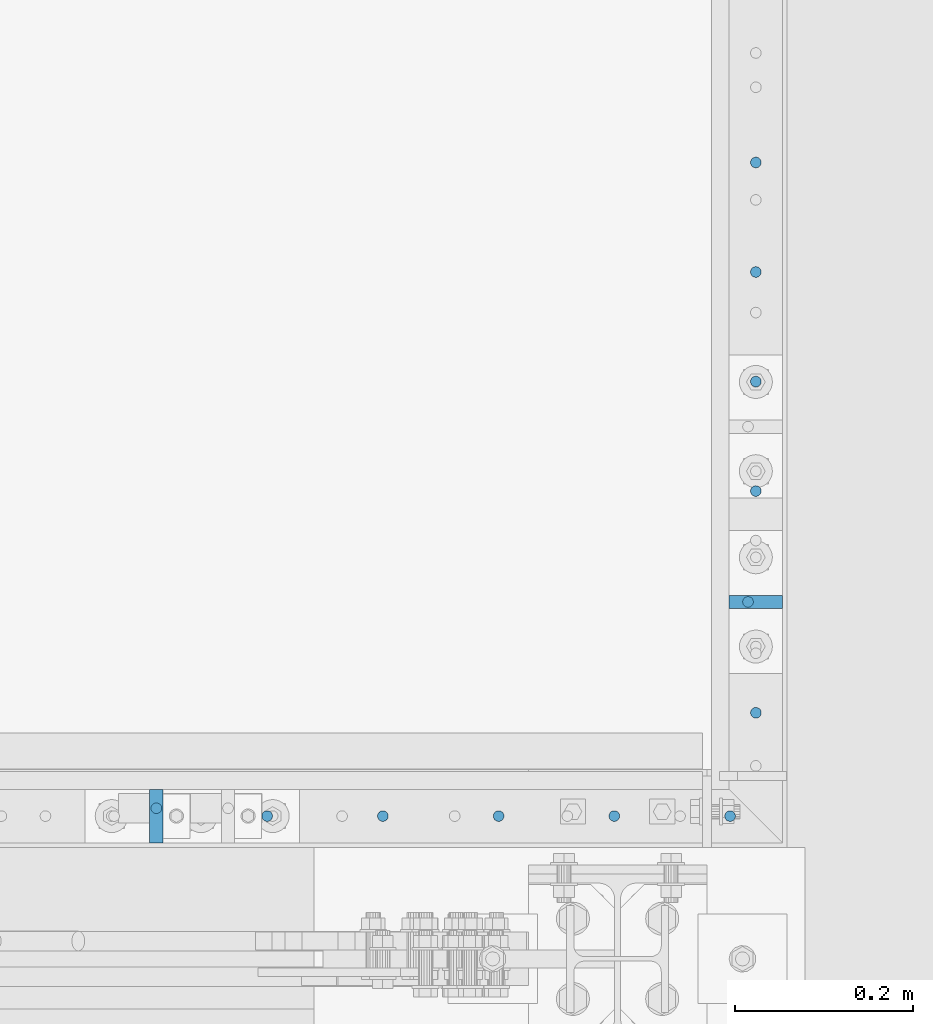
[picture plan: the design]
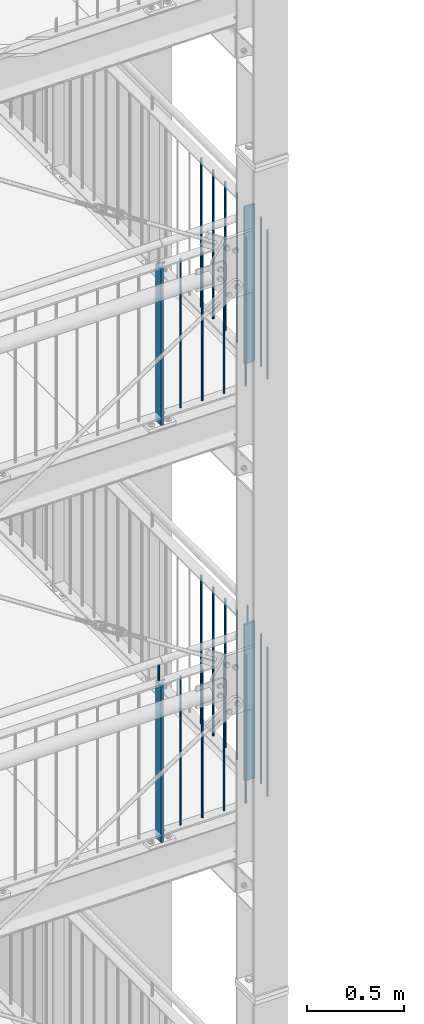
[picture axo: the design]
# One storey, part 88 of 825: 26 columns.
"""IFC2X3 building model written with IfcOpenShell, lengths in millimetres."""

from ifc_helpers import new_model, entity, si_unit, converted_unit, frame, origin, origin_with_axes, origin_2d, place, context, project, spatial, rectangle, circle, extrude, clip, halfspace, material, element, save


model = new_model("IFC2X3")

# Units and contexts
model_context = context("Model", 3, precision=1e-09, world=origin_with_axes())
ifc_project = project(units=[si_unit("LENGTHUNIT", "METRE", prefix="MILLI"), si_unit("AREAUNIT", "SQUARE_METRE"), si_unit("VOLUMEUNIT", "CUBIC_METRE"), converted_unit("PLANEANGLEUNIT", "DEGREE", entity("IfcPlaneAngleMeasure", 0.01745329), si_unit("PLANEANGLEUNIT", "RADIAN"), dimensions=[0, 0, 0, 0, 0, 0, 0])], contexts=[model_context])

# Site, building, storey
site_placement = place(None, origin_with_axes())
site = spatial("IfcSite", under=ifc_project, at=site_placement, CompositionType="ELEMENT")
building_placement = place(site_placement, origin_with_axes())
building = spatial("IfcBuilding", under=site, at=building_placement, Name="1", CompositionType="ELEMENT")
storey_placement = place(building_placement, origin_with_axes())
storey = spatial("IfcBuildingStorey", under=building, at=storey_placement, Name="Default Storey", CompositionType="ELEMENT", Elevation=0.0)

# Columns
ifc_material = material(Name="S235JR")
column_1_placement = place(None, frame((9021.713402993, 4766.735971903, 9675.723292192), z_axis=(0.0, 0.0, 1.0), x_axis=(0.0, -1.0, 0.0)))
element("IfcColumn", 1, at=column_1_placement, inside=storey, material=ifc_material, Name="Railing_Post_Landing#7", ObjectType="Railing_Post_Landing#7", context=model_context, shape_type="Clipping", body=[
    clip(clip(extrude(rectangle(XDim=15.0, YDim=60.0, at=origin_2d()), origin(), (0.0, 0.0, -1.0), 1070.646584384), halfspace(frame((4766.735971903, -9021.713402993, -1019.722292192), z_axis=(0.0, 0.0, 1.0), x_axis=(0.0, 1.0, 0.0)), True)), halfspace(frame((4766.735971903, -9021.713402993, -30.924292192), z_axis=(0.0, 0.0, -1.0), x_axis=(0.0, -1.0, 0.0)), True)),
])
column_2_placement = place(None, frame((8349.792260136, 4526.736971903, 9675.723292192), z_axis=(0.0, 0.0, 1.0), x_axis=(-1.0, 0.0, 0.0)))
element("IfcColumn", 2, at=column_2_placement, inside=storey, material=ifc_material, Name="Railing_Post_Landing#8", ObjectType="Railing_Post_Landing#8", context=model_context, shape_type="Clipping", body=[
    clip(clip(extrude(rectangle(XDim=15.0, YDim=60.0, at=origin_2d()), origin(), (0.0, 0.0, -1.0), 1070.646584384), halfspace(frame((8349.792260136, 4526.736971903, -1019.722292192), z_axis=(0.0, 0.0, 1.0), x_axis=(-1.0, 0.0, 0.0)), True)), halfspace(frame((8349.792260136, 4526.736971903, -30.924292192), z_axis=(0.0, 0.0, -1.0), x_axis=(1.0, 0.0, 0.0)), True)),
])
column_3_placement = place(None, frame((9021.713402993, 5259.236043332, 9658.285281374), z_axis=(0.0, 0.0, 1.0), x_axis=(0.0, -1.0, 0.0)))
element("IfcColumn", 3, at=column_3_placement, inside=storey, material=ifc_material, Name="Railing_Picket_Landing#45", ObjectType="Railing_Picket_Landing#45", context=model_context, shape_type="Clipping", body=[
    clip(clip(extrude(circle(Radius=6.0, at=origin_2d()), origin(), (0.0, 0.0, -1.0), 965.770562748), halfspace(frame((5259.236043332, -9021.713402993, -13.486281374), z_axis=(0.0, 0.0, -1.0), x_axis=(0.0, -1.0, 0.0)), True)), halfspace(frame((5259.236043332, -9021.713402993, -952.284281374), z_axis=(0.0, 0.0, 1.0), x_axis=(0.0, 1.0, 0.0)), True)),
])
column_4_placement = place(None, frame((9021.713402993, 5136.486019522, 9658.285281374), z_axis=(0.0, 0.0, 1.0), x_axis=(0.0, -1.0, 0.0)))
element("IfcColumn", 4, at=column_4_placement, inside=storey, material=ifc_material, Name="Railing_Picket_Landing#46", ObjectType="Railing_Picket_Landing#46", context=model_context, shape_type="Clipping", body=[
    clip(clip(extrude(circle(Radius=6.0, at=origin_2d()), origin(), (0.0, 0.0, -1.0), 965.770562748), halfspace(frame((5136.486019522, -9021.713402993, -13.486281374), z_axis=(0.0, 0.0, -1.0), x_axis=(0.0, -1.0, 0.0)), True)), halfspace(frame((5136.486019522, -9021.713402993, -952.284281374), z_axis=(0.0, 0.0, 1.0), x_axis=(0.0, 1.0, 0.0)), True)),
])
column_5_placement = place(None, frame((9021.713402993, 5013.735995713, 9658.285281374), z_axis=(0.0, 0.0, 1.0), x_axis=(0.0, -1.0, 0.0)))
element("IfcColumn", 5, at=column_5_placement, inside=storey, material=ifc_material, Name="Railing_Picket_Landing#47", ObjectType="Railing_Picket_Landing#47", context=model_context, shape_type="Clipping", body=[
    clip(clip(extrude(circle(Radius=6.0, at=origin_2d()), origin(), (0.0, 0.0, -1.0), 965.770562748), halfspace(frame((5013.735995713, -9021.713402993, -13.486281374), z_axis=(0.0, 0.0, -1.0), x_axis=(0.0, -1.0, 0.0)), True)), halfspace(frame((5013.735995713, -9021.713402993, -952.284281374), z_axis=(0.0, 0.0, 1.0), x_axis=(0.0, 1.0, 0.0)), True)),
])
column_6_placement = place(None, frame((9021.713402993, 4890.985971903, 9658.285281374), z_axis=(0.0, 0.0, 1.0), x_axis=(0.0, -1.0, 0.0)))
element("IfcColumn", 6, at=column_6_placement, inside=storey, material=ifc_material, Name="Railing_Picket_Landing#48", ObjectType="Railing_Picket_Landing#48", context=model_context, shape_type="Clipping", body=[
    clip(clip(extrude(circle(Radius=6.0, at=origin_2d()), origin(), (0.0, 0.0, -1.0), 965.770562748), halfspace(frame((4890.985971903, -9021.713402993, -13.486281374), z_axis=(0.0, 0.0, -1.0), x_axis=(0.0, -1.0, 0.0)), True)), halfspace(frame((4890.985971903, -9021.713402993, -952.284281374), z_axis=(0.0, 0.0, 1.0), x_axis=(0.0, 1.0, 0.0)), True)),
])
column_7_placement = place(None, frame((9021.713402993, 4642.485971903, 9658.285281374), z_axis=(0.0, 0.0, 1.0), x_axis=(0.0, -1.0, 0.0)))
element("IfcColumn", 7, at=column_7_placement, inside=storey, material=ifc_material, Name="Railing_Picket_Landing#49", ObjectType="Railing_Picket_Landing#49", context=model_context, shape_type="Clipping", body=[
    clip(clip(extrude(circle(Radius=6.0, at=origin_2d()), origin(), (0.0, 0.0, -1.0), 965.770562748), halfspace(frame((4642.485971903, -9021.713402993, -13.486281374), z_axis=(0.0, 0.0, -1.0), x_axis=(0.0, -1.0, 0.0)), True)), halfspace(frame((4642.485971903, -9021.713402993, -952.284281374), z_axis=(0.0, 0.0, 1.0), x_axis=(0.0, 1.0, 0.0)), True)),
])
column_8_placement = place(None, frame((8992.778374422, 4526.736971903, 9658.285281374), z_axis=(0.0, 0.0, 1.0), x_axis=(-1.0, 0.0, 0.0)))
element("IfcColumn", 8, at=column_8_placement, inside=storey, material=ifc_material, Name="Railing_Picket_Landing#50", ObjectType="Railing_Picket_Landing#50", context=model_context, shape_type="Clipping", body=[
    clip(clip(extrude(circle(Radius=6.0, at=origin_2d()), origin(), (0.0, 0.0, -1.0), 965.770562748), halfspace(frame((8992.778374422, 4526.736971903, -13.486281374), z_axis=(0.0, 0.0, -1.0), x_axis=(1.0, 0.0, 0.0)), True)), halfspace(frame((8992.778374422, 4526.736971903, -952.284281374), z_axis=(0.0, 0.0, 1.0), x_axis=(-1.0, 0.0, 0.0)), True)),
])
column_9_placement = place(None, frame((8863.09434585, 4526.736971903, 9658.285281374), z_axis=(0.0, 0.0, 1.0), x_axis=(-1.0, 0.0, 0.0)))
element("IfcColumn", 9, at=column_9_placement, inside=storey, material=ifc_material, Name="Railing_Picket_Landing#51", ObjectType="Railing_Picket_Landing#51", context=model_context, shape_type="Clipping", body=[
    clip(clip(extrude(circle(Radius=6.0, at=origin_2d()), origin(), (0.0, 0.0, -1.0), 965.770562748), halfspace(frame((8863.09434585, 4526.736971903, -13.486281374), z_axis=(0.0, 0.0, -1.0), x_axis=(1.0, 0.0, 0.0)), True)), halfspace(frame((8863.09434585, 4526.736971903, -952.284281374), z_axis=(0.0, 0.0, 1.0), x_axis=(-1.0, 0.0, 0.0)), True)),
])
column_10_placement = place(None, frame((8733.410317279, 4526.736971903, 9658.285281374), z_axis=(0.0, 0.0, 1.0), x_axis=(-1.0, 0.0, 0.0)))
element("IfcColumn", 10, at=column_10_placement, inside=storey, material=ifc_material, Name="Railing_Picket_Landing#52", ObjectType="Railing_Picket_Landing#52", context=model_context, shape_type="Clipping", body=[
    clip(clip(extrude(circle(Radius=6.0, at=origin_2d()), origin(), (0.0, 0.0, -1.0), 965.770562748), halfspace(frame((8733.410317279, 4526.736971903, -13.486281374), z_axis=(0.0, 0.0, -1.0), x_axis=(1.0, 0.0, 0.0)), True)), halfspace(frame((8733.410317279, 4526.736971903, -952.284281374), z_axis=(0.0, 0.0, 1.0), x_axis=(-1.0, 0.0, 0.0)), True)),
])
column_11_placement = place(None, frame((8603.726288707, 4526.736971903, 9658.285281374), z_axis=(0.0, 0.0, 1.0), x_axis=(-1.0, 0.0, 0.0)))
element("IfcColumn", 11, at=column_11_placement, inside=storey, material=ifc_material, Name="Railing_Picket_Landing#53", ObjectType="Railing_Picket_Landing#53", context=model_context, shape_type="Clipping", body=[
    clip(clip(extrude(circle(Radius=6.0, at=origin_2d()), origin(), (0.0, 0.0, -1.0), 965.770562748), halfspace(frame((8603.726288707, 4526.736971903, -13.486281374), z_axis=(0.0, 0.0, -1.0), x_axis=(1.0, 0.0, 0.0)), True)), halfspace(frame((8603.726288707, 4526.736971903, -952.284281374), z_axis=(0.0, 0.0, 1.0), x_axis=(-1.0, 0.0, 0.0)), True)),
])
column_12_placement = place(None, frame((8474.042260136, 4526.736971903, 9658.285281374), z_axis=(0.0, 0.0, 1.0), x_axis=(-1.0, 0.0, 0.0)))
element("IfcColumn", 12, at=column_12_placement, inside=storey, material=ifc_material, Name="Railing_Picket_Landing#54", ObjectType="Railing_Picket_Landing#54", context=model_context, shape_type="Clipping", body=[
    clip(clip(extrude(circle(Radius=6.0, at=origin_2d()), origin(), (0.0, 0.0, -1.0), 965.770562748), halfspace(frame((8474.042260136, 4526.736971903, -13.486281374), z_axis=(0.0, 0.0, -1.0), x_axis=(1.0, 0.0, 0.0)), True)), halfspace(frame((8474.042260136, 4526.736971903, -952.284281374), z_axis=(0.0, 0.0, 1.0), x_axis=(-1.0, 0.0, 0.0)), True)),
])
column_13_placement = place(None, frame((9012.913402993, 4766.735971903, 9763.285281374), z_axis=(0.0, 0.0, 1.0), x_axis=(-1.0, 0.0, 0.0)))
element("IfcColumn", 13, at=column_13_placement, inside=storey, material=ifc_material, Name="Bar#7", ObjectType="Bar#7", context=model_context, shape_type="Clipping", body=[
    clip(clip(extrude(circle(Radius=6.0, at=origin_2d()), origin(), (0.0, 0.0, -1.0), 116.970562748), halfspace(frame((9012.913402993, 4766.735971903, -8.486281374), z_axis=(0.0, 0.0, -1.0), x_axis=(1.0, 0.0, 0.0)), True)), halfspace(frame((9012.913402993, 4766.735971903, -108.484281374), z_axis=(0.0, 0.0, 1.0), x_axis=(-1.0, 0.0, 0.0)), True)),
])
column_14_placement = place(None, frame((8349.792260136, 4535.536971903, 9763.285281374), z_axis=(0.0, 0.0, 1.0), x_axis=(0.0, 1.0, 0.0)))
element("IfcColumn", 14, at=column_14_placement, inside=storey, material=ifc_material, Name="Bar#8", ObjectType="Bar#8", context=model_context, shape_type="Clipping", body=[
    clip(clip(extrude(circle(Radius=6.0, at=origin_2d()), origin(), (0.0, 0.0, -1.0), 116.970562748), halfspace(frame((-4535.536971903, 8349.792260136, -8.486281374), z_axis=(0.0, 0.0, -1.0), x_axis=(0.0, 1.0, 0.0)), True)), halfspace(frame((-4535.536971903, 8349.792260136, -108.484281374), z_axis=(0.0, 0.0, 1.0), x_axis=(0.0, -1.0, 0.0)), True)),
])
column_15_placement = place(None, frame((9021.713402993, 4766.735971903, 12305.223292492), z_axis=(0.0, 0.0, 1.0), x_axis=(0.0, -1.0, 0.0)))
element("IfcColumn", 15, at=column_15_placement, inside=storey, material=ifc_material, Name="Railing_Post_Landing#7", ObjectType="Railing_Post_Landing#7", context=model_context, shape_type="Clipping", body=[
    clip(clip(extrude(rectangle(XDim=15.0, YDim=60.0, at=origin_2d()), origin(), (0.0, 0.0, -1.0), 1070.646584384), halfspace(frame((4766.735971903, -9021.713402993, -1019.722292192), z_axis=(0.0, 0.0, 1.0), x_axis=(0.0, 1.0, 0.0)), True)), halfspace(frame((4766.735971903, -9021.713402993, -30.924292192), z_axis=(0.0, 0.0, -1.0), x_axis=(0.0, -1.0, 0.0)), True)),
])
column_16_placement = place(None, frame((8349.792260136, 4526.736971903, 12305.223292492), z_axis=(0.0, 0.0, 1.0), x_axis=(-1.0, 0.0, 0.0)))
element("IfcColumn", 16, at=column_16_placement, inside=storey, material=ifc_material, Name="Railing_Post_Landing#8", ObjectType="Railing_Post_Landing#8", context=model_context, shape_type="Clipping", body=[
    clip(clip(extrude(rectangle(XDim=15.0, YDim=60.0, at=origin_2d()), origin(), (0.0, 0.0, -1.0), 1070.646584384), halfspace(frame((8349.792260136, 4526.736971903, -1019.722292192), z_axis=(0.0, 0.0, 1.0), x_axis=(-1.0, 0.0, 0.0)), True)), halfspace(frame((8349.792260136, 4526.736971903, -30.924292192), z_axis=(0.0, 0.0, -1.0), x_axis=(1.0, 0.0, 0.0)), True)),
])
column_17_placement = place(None, frame((9021.713402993, 5259.236043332, 12287.785281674), z_axis=(0.0, 0.0, 1.0), x_axis=(0.0, -1.0, 0.0)))
element("IfcColumn", 17, at=column_17_placement, inside=storey, material=ifc_material, Name="Railing_Picket_Landing#45", ObjectType="Railing_Picket_Landing#45", context=model_context, shape_type="Clipping", body=[
    clip(clip(extrude(circle(Radius=6.0, at=origin_2d()), origin(), (0.0, 0.0, -1.0), 965.770562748), halfspace(frame((5259.236043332, -9021.713402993, -13.486281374), z_axis=(0.0, 0.0, -1.0), x_axis=(0.0, -1.0, 0.0)), True)), halfspace(frame((5259.236043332, -9021.713402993, -952.284281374), z_axis=(0.0, 0.0, 1.0), x_axis=(0.0, 1.0, 0.0)), True)),
])
column_18_placement = place(None, frame((9021.713402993, 5136.486019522, 12287.785281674), z_axis=(0.0, 0.0, 1.0), x_axis=(0.0, -1.0, 0.0)))
element("IfcColumn", 18, at=column_18_placement, inside=storey, material=ifc_material, Name="Railing_Picket_Landing#46", ObjectType="Railing_Picket_Landing#46", context=model_context, shape_type="Clipping", body=[
    clip(clip(extrude(circle(Radius=6.0, at=origin_2d()), origin(), (0.0, 0.0, -1.0), 965.770562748), halfspace(frame((5136.486019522, -9021.713402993, -13.486281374), z_axis=(0.0, 0.0, -1.0), x_axis=(0.0, -1.0, 0.0)), True)), halfspace(frame((5136.486019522, -9021.713402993, -952.284281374), z_axis=(0.0, 0.0, 1.0), x_axis=(0.0, 1.0, 0.0)), True)),
])
column_19_placement = place(None, frame((9021.713402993, 5013.735995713, 12287.785281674), z_axis=(0.0, 0.0, 1.0), x_axis=(0.0, -1.0, 0.0)))
element("IfcColumn", 19, at=column_19_placement, inside=storey, material=ifc_material, Name="Railing_Picket_Landing#47", ObjectType="Railing_Picket_Landing#47", context=model_context, shape_type="Clipping", body=[
    clip(clip(extrude(circle(Radius=6.0, at=origin_2d()), origin(), (0.0, 0.0, -1.0), 965.770562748), halfspace(frame((5013.735995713, -9021.713402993, -13.486281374), z_axis=(0.0, 0.0, -1.0), x_axis=(0.0, -1.0, 0.0)), True)), halfspace(frame((5013.735995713, -9021.713402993, -952.284281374), z_axis=(0.0, 0.0, 1.0), x_axis=(0.0, 1.0, 0.0)), True)),
])
column_20_placement = place(None, frame((9021.713402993, 4890.985971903, 12287.785281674), z_axis=(0.0, 0.0, 1.0), x_axis=(0.0, -1.0, 0.0)))
element("IfcColumn", 20, at=column_20_placement, inside=storey, material=ifc_material, Name="Railing_Picket_Landing#48", ObjectType="Railing_Picket_Landing#48", context=model_context, shape_type="Clipping", body=[
    clip(clip(extrude(circle(Radius=6.0, at=origin_2d()), origin(), (0.0, 0.0, -1.0), 965.770562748), halfspace(frame((4890.985971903, -9021.713402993, -13.486281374), z_axis=(0.0, 0.0, -1.0), x_axis=(0.0, -1.0, 0.0)), True)), halfspace(frame((4890.985971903, -9021.713402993, -952.284281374), z_axis=(0.0, 0.0, 1.0), x_axis=(0.0, 1.0, 0.0)), True)),
])
column_21_placement = place(None, frame((9021.713402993, 4642.485971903, 12287.785281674), z_axis=(0.0, 0.0, 1.0), x_axis=(0.0, -1.0, 0.0)))
element("IfcColumn", 21, at=column_21_placement, inside=storey, material=ifc_material, Name="Railing_Picket_Landing#49", ObjectType="Railing_Picket_Landing#49", context=model_context, shape_type="Clipping", body=[
    clip(clip(extrude(circle(Radius=6.0, at=origin_2d()), origin(), (0.0, 0.0, -1.0), 965.770562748), halfspace(frame((4642.485971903, -9021.713402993, -13.486281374), z_axis=(0.0, 0.0, -1.0), x_axis=(0.0, -1.0, 0.0)), True)), halfspace(frame((4642.485971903, -9021.713402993, -952.284281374), z_axis=(0.0, 0.0, 1.0), x_axis=(0.0, 1.0, 0.0)), True)),
])
column_22_placement = place(None, frame((8992.778374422, 4526.736971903, 12287.785281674), z_axis=(0.0, 0.0, 1.0), x_axis=(-1.0, 0.0, 0.0)))
element("IfcColumn", 22, at=column_22_placement, inside=storey, material=ifc_material, Name="Railing_Picket_Landing#50", ObjectType="Railing_Picket_Landing#50", context=model_context, shape_type="Clipping", body=[
    clip(clip(extrude(circle(Radius=6.0, at=origin_2d()), origin(), (0.0, 0.0, -1.0), 965.770562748), halfspace(frame((8992.778374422, 4526.736971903, -13.486281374), z_axis=(0.0, 0.0, -1.0), x_axis=(1.0, 0.0, 0.0)), True)), halfspace(frame((8992.778374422, 4526.736971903, -952.284281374), z_axis=(0.0, 0.0, 1.0), x_axis=(-1.0, 0.0, 0.0)), True)),
])
column_23_placement = place(None, frame((8863.09434585, 4526.736971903, 12287.785281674), z_axis=(0.0, 0.0, 1.0), x_axis=(-1.0, 0.0, 0.0)))
element("IfcColumn", 23, at=column_23_placement, inside=storey, material=ifc_material, Name="Railing_Picket_Landing#51", ObjectType="Railing_Picket_Landing#51", context=model_context, shape_type="Clipping", body=[
    clip(clip(extrude(circle(Radius=6.0, at=origin_2d()), origin(), (0.0, 0.0, -1.0), 965.770562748), halfspace(frame((8863.09434585, 4526.736971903, -13.486281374), z_axis=(0.0, 0.0, -1.0), x_axis=(1.0, 0.0, 0.0)), True)), halfspace(frame((8863.09434585, 4526.736971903, -952.284281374), z_axis=(0.0, 0.0, 1.0), x_axis=(-1.0, 0.0, 0.0)), True)),
])
column_24_placement = place(None, frame((8733.410317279, 4526.736971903, 12287.785281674), z_axis=(0.0, 0.0, 1.0), x_axis=(-1.0, 0.0, 0.0)))
element("IfcColumn", 24, at=column_24_placement, inside=storey, material=ifc_material, Name="Railing_Picket_Landing#52", ObjectType="Railing_Picket_Landing#52", context=model_context, shape_type="Clipping", body=[
    clip(clip(extrude(circle(Radius=6.0, at=origin_2d()), origin(), (0.0, 0.0, -1.0), 965.770562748), halfspace(frame((8733.410317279, 4526.736971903, -13.486281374), z_axis=(0.0, 0.0, -1.0), x_axis=(1.0, 0.0, 0.0)), True)), halfspace(frame((8733.410317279, 4526.736971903, -952.284281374), z_axis=(0.0, 0.0, 1.0), x_axis=(-1.0, 0.0, 0.0)), True)),
])
column_25_placement = place(None, frame((8603.726288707, 4526.736971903, 12287.785281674), z_axis=(0.0, 0.0, 1.0), x_axis=(-1.0, 0.0, 0.0)))
element("IfcColumn", 25, at=column_25_placement, inside=storey, material=ifc_material, Name="Railing_Picket_Landing#53", ObjectType="Railing_Picket_Landing#53", context=model_context, shape_type="Clipping", body=[
    clip(clip(extrude(circle(Radius=6.0, at=origin_2d()), origin(), (0.0, 0.0, -1.0), 965.770562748), halfspace(frame((8603.726288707, 4526.736971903, -13.486281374), z_axis=(0.0, 0.0, -1.0), x_axis=(1.0, 0.0, 0.0)), True)), halfspace(frame((8603.726288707, 4526.736971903, -952.284281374), z_axis=(0.0, 0.0, 1.0), x_axis=(-1.0, 0.0, 0.0)), True)),
])
column_26_placement = place(None, frame((8474.042260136, 4526.736971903, 12287.785281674), z_axis=(0.0, 0.0, 1.0), x_axis=(-1.0, 0.0, 0.0)))
element("IfcColumn", 26, at=column_26_placement, inside=storey, material=ifc_material, Name="Railing_Picket_Landing#54", ObjectType="Railing_Picket_Landing#54", context=model_context, shape_type="Clipping", body=[
    clip(clip(extrude(circle(Radius=6.0, at=origin_2d()), origin(), (0.0, 0.0, -1.0), 965.770562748), halfspace(frame((8474.042260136, 4526.736971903, -13.486281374), z_axis=(0.0, 0.0, -1.0), x_axis=(1.0, 0.0, 0.0)), True)), halfspace(frame((8474.042260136, 4526.736971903, -952.284281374), z_axis=(0.0, 0.0, 1.0), x_axis=(-1.0, 0.0, 0.0)), True)),
])

save(model, "model.ifc")
